##
## LEF for PtnCells ;
## created by Innovus v15.23-s045_1 on Thu Mar  5 12:03:12 2026
##

VERSION 5.8 ;

BUSBITCHARS "[]" ;
DIVIDERCHAR "/" ;

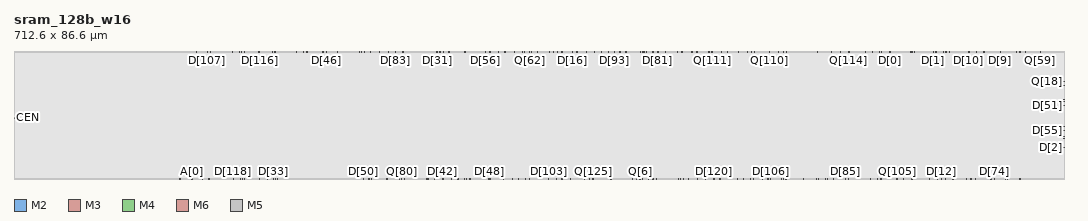
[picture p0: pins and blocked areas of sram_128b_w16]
MACRO sram_128b_w16
  CLASS BLOCK ;
  SIZE 712.6000 BY 86.6000 ;
  FOREIGN sram_128b_w16 0.0000 0.0000 ;
  ORIGIN 0 0 ;
  SYMMETRY X Y R90 ;
  PIN CLK
    DIRECTION INPUT ;
    USE SIGNAL ;
    PORT
      LAYER M2 ;
        RECT 429.4500 86.0800 429.5500 86.6000 ;
    END
  END CLK
  PIN D[127]
    DIRECTION INPUT ;
    USE SIGNAL ;
    PORT
      LAYER M2 ;
        RECT 608.6500 86.0800 608.7500 86.6000 ;
    END
  END D[127]
  PIN D[126]
    DIRECTION INPUT ;
    USE SIGNAL ;
    PORT
      LAYER M2 ;
        RECT 132.2500 0.0000 132.3500 0.5200 ;
    END
  END D[126]
  PIN D[125]
    DIRECTION INPUT ;
    USE SIGNAL ;
    PORT
      LAYER M2 ;
        RECT 390.6500 0.0000 390.7500 0.5200 ;
    END
  END D[125]
  PIN D[124]
    DIRECTION INPUT ;
    USE SIGNAL ;
    PORT
      LAYER M2 ;
        RECT 535.8500 0.0000 535.9500 0.5200 ;
    END
  END D[124]
  PIN D[123]
    DIRECTION INPUT ;
    USE SIGNAL ;
    PORT
      LAYER M2 ;
        RECT 281.4500 0.0000 281.5500 0.5200 ;
    END
  END D[123]
  PIN D[122]
    DIRECTION INPUT ;
    USE SIGNAL ;
    PORT
      LAYER M2 ;
        RECT 153.8500 0.0000 153.9500 0.5200 ;
    END
  END D[122]
  PIN D[121]
    DIRECTION INPUT ;
    USE SIGNAL ;
    PORT
      LAYER M2 ;
        RECT 546.0500 0.0000 546.1500 0.5200 ;
    END
  END D[121]
  PIN D[120]
    DIRECTION INPUT ;
    USE SIGNAL ;
    PORT
      LAYER M2 ;
        RECT 475.0500 0.0000 475.1500 0.5200 ;
    END
  END D[120]
  PIN D[119]
    DIRECTION INPUT ;
    USE SIGNAL ;
    PORT
      LAYER M2 ;
        RECT 554.6500 86.0800 554.7500 86.6000 ;
    END
  END D[119]
  PIN D[118]
    DIRECTION INPUT ;
    USE SIGNAL ;
    PORT
      LAYER M2 ;
        RECT 148.8500 0.0000 148.9500 0.5200 ;
    END
  END D[118]
  PIN D[117]
    DIRECTION INPUT ;
    USE SIGNAL ;
    PORT
      LAYER M2 ;
        RECT 453.4500 86.0800 453.5500 86.6000 ;
    END
  END D[117]
  PIN D[116]
    DIRECTION INPUT ;
    USE SIGNAL ;
    PORT
      LAYER M2 ;
        RECT 166.8500 86.0800 166.9500 86.6000 ;
    END
  END D[116]
  PIN D[115]
    DIRECTION INPUT ;
    USE SIGNAL ;
    PORT
      LAYER M2 ;
        RECT 478.6500 0.0000 478.7500 0.5200 ;
    END
  END D[115]
  PIN D[114]
    DIRECTION INPUT ;
    USE SIGNAL ;
    PORT
      LAYER M2 ;
        RECT 560.6500 86.0800 560.7500 86.6000 ;
    END
  END D[114]
  PIN D[113]
    DIRECTION INPUT ;
    USE SIGNAL ;
    PORT
      LAYER M2 ;
        RECT 545.2500 86.0800 545.3500 86.6000 ;
    END
  END D[113]
  PIN D[112]
    DIRECTION INPUT ;
    USE SIGNAL ;
    PORT
      LAYER M2 ;
        RECT 522.0500 86.0800 522.1500 86.6000 ;
    END
  END D[112]
  PIN D[111]
    DIRECTION INPUT ;
    USE SIGNAL ;
    PORT
      LAYER M2 ;
        RECT 471.6500 86.0800 471.7500 86.6000 ;
    END
  END D[111]
  PIN D[110]
    DIRECTION INPUT ;
    USE SIGNAL ;
    PORT
      LAYER M2 ;
        RECT 502.6500 86.0800 502.7500 86.6000 ;
    END
  END D[110]
  PIN D[109]
    DIRECTION INPUT ;
    USE SIGNAL ;
    PORT
      LAYER M2 ;
        RECT 291.6500 86.0800 291.7500 86.6000 ;
    END
  END D[109]
  PIN D[108]
    DIRECTION INPUT ;
    USE SIGNAL ;
    PORT
      LAYER M2 ;
        RECT 578.0500 86.0800 578.1500 86.6000 ;
    END
  END D[108]
  PIN D[107]
    DIRECTION INPUT ;
    USE SIGNAL ;
    PORT
      LAYER M2 ;
        RECT 131.2500 86.0800 131.3500 86.6000 ;
    END
  END D[107]
  PIN D[106]
    DIRECTION INPUT ;
    USE SIGNAL ;
    PORT
      LAYER M2 ;
        RECT 513.4500 0.0000 513.5500 0.5200 ;
    END
  END D[106]
  PIN D[105]
    DIRECTION INPUT ;
    USE SIGNAL ;
    PORT
      LAYER M2 ;
        RECT 599.2500 0.0000 599.3500 0.5200 ;
    END
  END D[105]
  PIN D[104]
    DIRECTION INPUT ;
    USE SIGNAL ;
    PORT
      LAYER M2 ;
        RECT 609.0500 0.0000 609.1500 0.5200 ;
    END
  END D[104]
  PIN D[103]
    DIRECTION INPUT ;
    USE SIGNAL ;
    PORT
      LAYER M2 ;
        RECT 362.8500 0.0000 362.9500 0.5200 ;
    END
  END D[103]
  PIN D[102]
    DIRECTION INPUT ;
    USE SIGNAL ;
    PORT
      LAYER M2 ;
        RECT 491.2500 0.0000 491.3500 0.5200 ;
    END
  END D[102]
  PIN D[101]
    DIRECTION INPUT ;
    USE SIGNAL ;
    PORT
      LAYER M2 ;
        RECT 520.8500 0.0000 520.9500 0.5200 ;
    END
  END D[101]
  PIN D[100]
    DIRECTION INPUT ;
    USE SIGNAL ;
    PORT
      LAYER M2 ;
        RECT 148.4500 86.0800 148.5500 86.6000 ;
    END
  END D[100]
  PIN D[99]
    DIRECTION INPUT ;
    USE SIGNAL ;
    PORT
      LAYER M2 ;
        RECT 219.6500 86.0800 219.7500 86.6000 ;
    END
  END D[99]
  PIN D[98]
    DIRECTION INPUT ;
    USE SIGNAL ;
    PORT
      LAYER M2 ;
        RECT 621.2500 0.0000 621.3500 0.5200 ;
    END
  END D[98]
  PIN D[97]
    DIRECTION INPUT ;
    USE SIGNAL ;
    PORT
      LAYER M2 ;
        RECT 237.2500 0.0000 237.3500 0.5200 ;
    END
  END D[97]
  PIN D[96]
    DIRECTION INPUT ;
    USE SIGNAL ;
    PORT
      LAYER M2 ;
        RECT 411.2500 86.0800 411.3500 86.6000 ;
    END
  END D[96]
  PIN D[95]
    DIRECTION INPUT ;
    USE SIGNAL ;
    PORT
      LAYER M2 ;
        RECT 508.0500 0.0000 508.1500 0.5200 ;
    END
  END D[95]
  PIN D[94]
    DIRECTION INPUT ;
    USE SIGNAL ;
    PORT
      LAYER M2 ;
        RECT 500.0500 0.0000 500.1500 0.5200 ;
    END
  END D[94]
  PIN D[93]
    DIRECTION INPUT ;
    USE SIGNAL ;
    PORT
      LAYER M2 ;
        RECT 407.2500 86.0800 407.3500 86.6000 ;
    END
  END D[93]
  PIN D[92]
    DIRECTION INPUT ;
    USE SIGNAL ;
    PORT
      LAYER M2 ;
        RECT 646.4500 0.0000 646.5500 0.5200 ;
    END
  END D[92]
  PIN D[91]
    DIRECTION INPUT ;
    USE SIGNAL ;
    PORT
      LAYER M2 ;
        RECT 363.2500 86.0800 363.3500 86.6000 ;
    END
  END D[91]
  PIN D[90]
    DIRECTION INPUT ;
    USE SIGNAL ;
    PORT
      LAYER M2 ;
        RECT 388.4500 86.0800 388.5500 86.6000 ;
    END
  END D[90]
  PIN D[89]
    DIRECTION INPUT ;
    USE SIGNAL ;
    PORT
      LAYER M2 ;
        RECT 294.6500 86.0800 294.7500 86.6000 ;
    END
  END D[89]
  PIN D[88]
    DIRECTION INPUT ;
    USE SIGNAL ;
    PORT
      LAYER M2 ;
        RECT 368.2500 0.0000 368.3500 0.5200 ;
    END
  END D[88]
  PIN D[87]
    DIRECTION INPUT ;
    USE SIGNAL ;
    PORT
      LAYER M2 ;
        RECT 433.6500 0.0000 433.7500 0.5200 ;
    END
  END D[87]
  PIN D[86]
    DIRECTION INPUT ;
    USE SIGNAL ;
    PORT
      LAYER M2 ;
        RECT 649.6500 0.0000 649.7500 0.5200 ;
    END
  END D[86]
  PIN D[85]
    DIRECTION INPUT ;
    USE SIGNAL ;
    PORT
      LAYER M2 ;
        RECT 564.4500 0.0000 564.5500 0.5200 ;
    END
  END D[85]
  PIN D[84]
    DIRECTION INPUT ;
    USE SIGNAL ;
    PORT
      LAYER M2 ;
        RECT 653.2500 86.0800 653.3500 86.6000 ;
    END
  END D[84]
  PIN D[83]
    DIRECTION INPUT ;
    USE SIGNAL ;
    PORT
      LAYER M2 ;
        RECT 259.0500 86.0800 259.1500 86.6000 ;
    END
  END D[83]
  PIN D[82]
    DIRECTION INPUT ;
    USE SIGNAL ;
    PORT
      LAYER M2 ;
        RECT 234.4500 86.0800 234.5500 86.6000 ;
    END
  END D[82]
  PIN D[81]
    DIRECTION INPUT ;
    USE SIGNAL ;
    PORT
      LAYER M2 ;
        RECT 436.8500 86.0800 436.9500 86.6000 ;
    END
  END D[81]
  PIN D[80]
    DIRECTION INPUT ;
    USE SIGNAL ;
    PORT
      LAYER M2 ;
        RECT 261.6500 0.0000 261.7500 0.5200 ;
    END
  END D[80]
  PIN D[79]
    DIRECTION INPUT ;
    USE SIGNAL ;
    PORT
      LAYER M2 ;
        RECT 191.4500 86.0800 191.5500 86.6000 ;
    END
  END D[79]
  PIN D[78]
    DIRECTION INPUT ;
    USE SIGNAL ;
    PORT
      LAYER M2 ;
        RECT 635.0500 86.0800 635.1500 86.6000 ;
    END
  END D[78]
  PIN D[77]
    DIRECTION INPUT ;
    USE SIGNAL ;
    PORT
      LAYER M2 ;
        RECT 342.2500 0.0000 342.3500 0.5200 ;
    END
  END D[77]
  PIN D[76]
    DIRECTION INPUT ;
    USE SIGNAL ;
    PORT
      LAYER M2 ;
        RECT 248.0500 86.0800 248.1500 86.6000 ;
    END
  END D[76]
  PIN D[75]
    DIRECTION INPUT ;
    USE SIGNAL ;
    PORT
      LAYER M2 ;
        RECT 196.4500 86.0800 196.5500 86.6000 ;
    END
  END D[75]
  PIN D[74]
    DIRECTION INPUT ;
    USE SIGNAL ;
    PORT
      LAYER M2 ;
        RECT 665.4500 0.0000 665.5500 0.5200 ;
    END
  END D[74]
  PIN D[73]
    DIRECTION INPUT ;
    USE SIGNAL ;
    PORT
      LAYER M2 ;
        RECT 323.4500 0.0000 323.5500 0.5200 ;
    END
  END D[73]
  PIN D[72]
    DIRECTION INPUT ;
    USE SIGNAL ;
    PORT
      LAYER M2 ;
        RECT 333.4500 86.0800 333.5500 86.6000 ;
    END
  END D[72]
  PIN D[71]
    DIRECTION INPUT ;
    USE SIGNAL ;
    PORT
      LAYER M2 ;
        RECT 424.2500 0.0000 424.3500 0.5200 ;
    END
  END D[71]
  PIN D[70]
    DIRECTION INPUT ;
    USE SIGNAL ;
    PORT
      LAYER M2 ;
        RECT 309.4500 0.0000 309.5500 0.5200 ;
    END
  END D[70]
  PIN D[69]
    DIRECTION INPUT ;
    USE SIGNAL ;
    PORT
      LAYER M2 ;
        RECT 680.0500 86.0800 680.1500 86.6000 ;
    END
  END D[69]
  PIN D[68]
    DIRECTION INPUT ;
    USE SIGNAL ;
    PORT
      LAYER M2 ;
        RECT 405.6500 0.0000 405.7500 0.5200 ;
    END
  END D[68]
  PIN D[67]
    DIRECTION INPUT ;
    USE SIGNAL ;
    PORT
      LAYER M2 ;
        RECT 347.0500 0.0000 347.1500 0.5200 ;
    END
  END D[67]
  PIN D[66]
    DIRECTION INPUT ;
    USE SIGNAL ;
    PORT
      LAYER M2 ;
        RECT 377.4500 0.0000 377.5500 0.5200 ;
    END
  END D[66]
  PIN D[65]
    DIRECTION INPUT ;
    USE SIGNAL ;
    PORT
      LAYER M2 ;
        RECT 323.0500 86.0800 323.1500 86.6000 ;
    END
  END D[65]
  PIN D[64]
    DIRECTION INPUT ;
    USE SIGNAL ;
    PORT
      LAYER M2 ;
        RECT 301.2500 0.0000 301.3500 0.5200 ;
    END
  END D[64]
  PIN D[63]
    DIRECTION INPUT ;
    USE SIGNAL ;
    PORT
      LAYER M2 ;
        RECT 637.2500 0.0000 637.3500 0.5200 ;
    END
  END D[63]
  PIN D[62]
    DIRECTION INPUT ;
    USE SIGNAL ;
    PORT
      LAYER M2 ;
        RECT 346.6500 86.0800 346.7500 86.6000 ;
    END
  END D[62]
  PIN D[61]
    DIRECTION INPUT ;
    USE SIGNAL ;
    PORT
      LAYER M2 ;
        RECT 153.0500 86.0800 153.1500 86.6000 ;
    END
  END D[61]
  PIN D[60]
    DIRECTION INPUT ;
    USE SIGNAL ;
    PORT
      LAYER M2 ;
        RECT 178.8500 0.0000 178.9500 0.5200 ;
    END
  END D[60]
  PIN D[59]
    DIRECTION INPUT ;
    USE SIGNAL ;
    PORT
      LAYER M2 ;
        RECT 682.2500 86.0800 682.3500 86.6000 ;
    END
  END D[59]
  PIN D[58]
    DIRECTION INPUT ;
    USE SIGNAL ;
    PORT
      LAYER M2 ;
        RECT 166.6500 0.0000 166.7500 0.5200 ;
    END
  END D[58]
  PIN D[57]
    DIRECTION INPUT ;
    USE SIGNAL ;
    PORT
      LAYER M2 ;
        RECT 552.2500 0.0000 552.3500 0.5200 ;
    END
  END D[57]
  PIN D[56]
    DIRECTION INPUT ;
    USE SIGNAL ;
    PORT
      LAYER M2 ;
        RECT 320.0500 86.0800 320.1500 86.6000 ;
    END
  END D[56]
  PIN D[55]
    DIRECTION INPUT ;
    USE SIGNAL ;
    PORT
      LAYER M3 ;
        RECT 712.0800 32.9500 712.6000 33.0500 ;
    END
  END D[55]
  PIN D[54]
    DIRECTION INPUT ;
    USE SIGNAL ;
    PORT
      LAYER M2 ;
        RECT 332.0500 0.0000 332.1500 0.5200 ;
    END
  END D[54]
  PIN D[53]
    DIRECTION INPUT ;
    USE SIGNAL ;
    PORT
      LAYER M2 ;
        RECT 427.6500 86.0800 427.7500 86.6000 ;
    END
  END D[53]
  PIN D[52]
    DIRECTION INPUT ;
    USE SIGNAL ;
    PORT
      LAYER M4 ;
        RECT 347.2500 0.0000 347.3500 0.5200 ;
    END
  END D[52]
  PIN D[51]
    DIRECTION INPUT ;
    USE SIGNAL ;
    PORT
      LAYER M3 ;
        RECT 712.0800 49.5500 712.6000 49.6500 ;
    END
  END D[51]
  PIN D[50]
    DIRECTION INPUT ;
    USE SIGNAL ;
    PORT
      LAYER M4 ;
        RECT 237.0500 0.0000 237.1500 0.5200 ;
    END
  END D[50]
  PIN D[49]
    DIRECTION INPUT ;
    USE SIGNAL ;
    PORT
      LAYER M2 ;
        RECT 237.8500 86.0800 237.9500 86.6000 ;
    END
  END D[49]
  PIN D[48]
    DIRECTION INPUT ;
    USE SIGNAL ;
    PORT
      LAYER M2 ;
        RECT 322.8500 0.0000 322.9500 0.5200 ;
    END
  END D[48]
  PIN D[47]
    DIRECTION INPUT ;
    USE SIGNAL ;
    PORT
      LAYER M2 ;
        RECT 387.2500 0.0000 387.3500 0.5200 ;
    END
  END D[47]
  PIN D[46]
    DIRECTION INPUT ;
    USE SIGNAL ;
    PORT
      LAYER M2 ;
        RECT 212.2500 86.0800 212.3500 86.6000 ;
    END
  END D[46]
  PIN D[45]
    DIRECTION INPUT ;
    USE SIGNAL ;
    PORT
      LAYER M2 ;
        RECT 454.4500 0.0000 454.5500 0.5200 ;
    END
  END D[45]
  PIN D[44]
    DIRECTION INPUT ;
    USE SIGNAL ;
    PORT
      LAYER M2 ;
        RECT 265.2500 0.0000 265.3500 0.5200 ;
    END
  END D[44]
  PIN D[43]
    DIRECTION INPUT ;
    USE SIGNAL ;
    PORT
      LAYER M2 ;
        RECT 252.6500 0.0000 252.7500 0.5200 ;
    END
  END D[43]
  PIN D[42]
    DIRECTION INPUT ;
    USE SIGNAL ;
    PORT
      LAYER M2 ;
        RECT 291.0500 0.0000 291.1500 0.5200 ;
    END
  END D[42]
  PIN D[41]
    DIRECTION INPUT ;
    USE SIGNAL ;
    PORT
      LAYER M2 ;
        RECT 280.2500 0.0000 280.3500 0.5200 ;
    END
  END D[41]
  PIN D[40]
    DIRECTION INPUT ;
    USE SIGNAL ;
    PORT
      LAYER M2 ;
        RECT 288.6500 86.0800 288.7500 86.6000 ;
    END
  END D[40]
  PIN D[39]
    DIRECTION INPUT ;
    USE SIGNAL ;
    PORT
      LAYER M2 ;
        RECT 289.6500 86.0800 289.7500 86.6000 ;
    END
  END D[39]
  PIN D[38]
    DIRECTION INPUT ;
    USE SIGNAL ;
    PORT
      LAYER M2 ;
        RECT 473.4500 86.0800 473.5500 86.6000 ;
    END
  END D[38]
  PIN D[37]
    DIRECTION INPUT ;
    USE SIGNAL ;
    PORT
      LAYER M2 ;
        RECT 175.4500 86.0800 175.5500 86.6000 ;
    END
  END D[37]
  PIN D[36]
    DIRECTION INPUT ;
    USE SIGNAL ;
    PORT
      LAYER M2 ;
        RECT 581.0500 0.0000 581.1500 0.5200 ;
    END
  END D[36]
  PIN D[35]
    DIRECTION INPUT ;
    USE SIGNAL ;
    PORT
      LAYER M2 ;
        RECT 351.2500 86.0800 351.3500 86.6000 ;
    END
  END D[35]
  PIN D[34]
    DIRECTION INPUT ;
    USE SIGNAL ;
    PORT
      LAYER M2 ;
        RECT 133.0500 86.0800 133.1500 86.6000 ;
    END
  END D[34]
  PIN D[33]
    DIRECTION INPUT ;
    USE SIGNAL ;
    PORT
      LAYER M2 ;
        RECT 175.8500 0.0000 175.9500 0.5200 ;
    END
  END D[33]
  PIN D[32]
    DIRECTION INPUT ;
    USE SIGNAL ;
    PORT
      LAYER M2 ;
        RECT 682.6500 0.0000 682.7500 0.5200 ;
    END
  END D[32]
  PIN D[31]
    DIRECTION INPUT ;
    USE SIGNAL ;
    PORT
      LAYER M2 ;
        RECT 287.0500 86.0800 287.1500 86.6000 ;
    END
  END D[31]
  PIN D[30]
    DIRECTION INPUT ;
    USE SIGNAL ;
    PORT
      LAYER M2 ;
        RECT 625.6500 86.0800 625.7500 86.6000 ;
    END
  END D[30]
  PIN D[29]
    DIRECTION INPUT ;
    USE SIGNAL ;
    PORT
      LAYER M2 ;
        RECT 586.0500 0.0000 586.1500 0.5200 ;
    END
  END D[29]
  PIN D[28]
    DIRECTION INPUT ;
    USE SIGNAL ;
    PORT
      LAYER M2 ;
        RECT 369.0500 86.0800 369.1500 86.6000 ;
    END
  END D[28]
  PIN D[27]
    DIRECTION INPUT ;
    USE SIGNAL ;
    PORT
      LAYER M2 ;
        RECT 393.6500 86.0800 393.7500 86.6000 ;
    END
  END D[27]
  PIN D[26]
    DIRECTION INPUT ;
    USE SIGNAL ;
    PORT
      LAYER M2 ;
        RECT 523.4500 0.0000 523.5500 0.5200 ;
    END
  END D[26]
  PIN D[25]
    DIRECTION INPUT ;
    USE SIGNAL ;
    PORT
      LAYER M2 ;
        RECT 460.2500 86.0800 460.3500 86.6000 ;
    END
  END D[25]
  PIN D[24]
    DIRECTION INPUT ;
    USE SIGNAL ;
    PORT
      LAYER M2 ;
        RECT 497.8500 86.0800 497.9500 86.6000 ;
    END
  END D[24]
  PIN D[23]
    DIRECTION INPUT ;
    USE SIGNAL ;
    PORT
      LAYER M2 ;
        RECT 450.4500 86.0800 450.5500 86.6000 ;
    END
  END D[23]
  PIN D[22]
    DIRECTION INPUT ;
    USE SIGNAL ;
    PORT
      LAYER M2 ;
        RECT 450.8500 0.0000 450.9500 0.5200 ;
    END
  END D[22]
  PIN D[21]
    DIRECTION INPUT ;
    USE SIGNAL ;
    PORT
      LAYER M2 ;
        RECT 603.6500 0.0000 603.7500 0.5200 ;
    END
  END D[21]
  PIN D[20]
    DIRECTION INPUT ;
    USE SIGNAL ;
    PORT
      LAYER M2 ;
        RECT 480.2500 86.0800 480.3500 86.6000 ;
    END
  END D[20]
  PIN D[19]
    DIRECTION INPUT ;
    USE SIGNAL ;
    PORT
      LAYER M2 ;
        RECT 463.6500 0.0000 463.7500 0.5200 ;
    END
  END D[19]
  PIN D[18]
    DIRECTION INPUT ;
    USE SIGNAL ;
    PORT
      LAYER M2 ;
        RECT 683.2500 86.0800 683.3500 86.6000 ;
    END
  END D[18]
  PIN D[17]
    DIRECTION INPUT ;
    USE SIGNAL ;
    PORT
      LAYER M2 ;
        RECT 518.8500 86.0800 518.9500 86.6000 ;
    END
  END D[17]
  PIN D[16]
    DIRECTION INPUT ;
    USE SIGNAL ;
    PORT
      LAYER M2 ;
        RECT 378.8500 86.0800 378.9500 86.6000 ;
    END
  END D[16]
  PIN D[15]
    DIRECTION INPUT ;
    USE SIGNAL ;
    PORT
      LAYER M2 ;
        RECT 415.2500 86.0800 415.3500 86.6000 ;
    END
  END D[15]
  PIN D[14]
    DIRECTION INPUT ;
    USE SIGNAL ;
    PORT
      LAYER M2 ;
        RECT 672.8500 0.0000 672.9500 0.5200 ;
    END
  END D[14]
  PIN D[13]
    DIRECTION INPUT ;
    USE SIGNAL ;
    PORT
      LAYER M2 ;
        RECT 433.6500 86.0800 433.7500 86.6000 ;
    END
  END D[13]
  PIN D[12]
    DIRECTION INPUT ;
    USE SIGNAL ;
    PORT
      LAYER M2 ;
        RECT 629.4500 0.0000 629.5500 0.5200 ;
    END
  END D[12]
  PIN D[11]
    DIRECTION INPUT ;
    USE SIGNAL ;
    PORT
      LAYER M2 ;
        RECT 649.2500 0.0000 649.3500 0.5200 ;
    END
  END D[11]
  PIN D[10]
    DIRECTION INPUT ;
    USE SIGNAL ;
    PORT
      LAYER M2 ;
        RECT 647.4500 86.0800 647.5500 86.6000 ;
    END
  END D[10]
  PIN D[9]
    DIRECTION INPUT ;
    USE SIGNAL ;
    PORT
      LAYER M2 ;
        RECT 669.2500 86.0800 669.3500 86.6000 ;
    END
  END D[9]
  PIN D[8]
    DIRECTION INPUT ;
    USE SIGNAL ;
    PORT
      LAYER M2 ;
        RECT 491.4500 86.0800 491.5500 86.6000 ;
    END
  END D[8]
  PIN D[7]
    DIRECTION INPUT ;
    USE SIGNAL ;
    PORT
      LAYER M2 ;
        RECT 686.2500 86.0800 686.3500 86.6000 ;
    END
  END D[7]
  PIN D[6]
    DIRECTION INPUT ;
    USE SIGNAL ;
    PORT
      LAYER M2 ;
        RECT 419.6500 0.0000 419.7500 0.5200 ;
    END
  END D[6]
  PIN D[5]
    DIRECTION INPUT ;
    USE SIGNAL ;
    PORT
      LAYER M2 ;
        RECT 422.6500 0.0000 422.7500 0.5200 ;
    END
  END D[5]
  PIN D[4]
    DIRECTION INPUT ;
    USE SIGNAL ;
    PORT
      LAYER M2 ;
        RECT 611.2500 86.0800 611.3500 86.6000 ;
    END
  END D[4]
  PIN D[3]
    DIRECTION INPUT ;
    USE SIGNAL ;
    PORT
      LAYER M2 ;
        RECT 587.4500 86.0800 587.5500 86.6000 ;
    END
  END D[3]
  PIN D[2]
    DIRECTION INPUT ;
    USE SIGNAL ;
    PORT
      LAYER M3 ;
        RECT 712.0800 21.5500 712.6000 21.6500 ;
    END
  END D[2]
  PIN D[1]
    DIRECTION INPUT ;
    USE SIGNAL ;
    PORT
      LAYER M2 ;
        RECT 623.8500 86.0800 623.9500 86.6000 ;
    END
  END D[1]
  PIN D[0]
    DIRECTION INPUT ;
    USE SIGNAL ;
    PORT
      LAYER M2 ;
        RECT 594.4500 86.0800 594.5500 86.6000 ;
    END
  END D[0]
  PIN Q[127]
    DIRECTION OUTPUT ;
    USE SIGNAL ;
    PORT
      LAYER M2 ;
        RECT 609.6500 86.0800 609.7500 86.6000 ;
    END
  END Q[127]
  PIN Q[126]
    DIRECTION OUTPUT ;
    USE SIGNAL ;
    PORT
      LAYER M2 ;
        RECT 127.8500 0.0000 127.9500 0.5200 ;
    END
  END Q[126]
  PIN Q[125]
    DIRECTION OUTPUT ;
    USE SIGNAL ;
    PORT
      LAYER M2 ;
        RECT 393.0500 0.0000 393.1500 0.5200 ;
    END
  END Q[125]
  PIN Q[124]
    DIRECTION OUTPUT ;
    USE SIGNAL ;
    PORT
      LAYER M2 ;
        RECT 544.6500 0.0000 544.7500 0.5200 ;
    END
  END Q[124]
  PIN Q[123]
    DIRECTION OUTPUT ;
    USE SIGNAL ;
    PORT
      LAYER M2 ;
        RECT 285.4500 0.0000 285.5500 0.5200 ;
    END
  END Q[123]
  PIN Q[122]
    DIRECTION OUTPUT ;
    USE SIGNAL ;
    PORT
      LAYER M2 ;
        RECT 156.6500 0.0000 156.7500 0.5200 ;
    END
  END Q[122]
  PIN Q[121]
    DIRECTION OUTPUT ;
    USE SIGNAL ;
    PORT
      LAYER M2 ;
        RECT 550.6500 0.0000 550.7500 0.5200 ;
    END
  END Q[121]
  PIN Q[120]
    DIRECTION OUTPUT ;
    USE SIGNAL ;
    PORT
      LAYER M2 ;
        RECT 479.6500 0.0000 479.7500 0.5200 ;
    END
  END Q[120]
  PIN Q[119]
    DIRECTION OUTPUT ;
    USE SIGNAL ;
    PORT
      LAYER M2 ;
        RECT 566.8500 86.0800 566.9500 86.6000 ;
    END
  END Q[119]
  PIN Q[118]
    DIRECTION OUTPUT ;
    USE SIGNAL ;
    PORT
      LAYER M2 ;
        RECT 155.0500 0.0000 155.1500 0.5200 ;
    END
  END Q[118]
  PIN Q[117]
    DIRECTION OUTPUT ;
    USE SIGNAL ;
    PORT
      LAYER M2 ;
        RECT 459.8500 86.0800 459.9500 86.6000 ;
    END
  END Q[117]
  PIN Q[116]
    DIRECTION OUTPUT ;
    USE SIGNAL ;
    PORT
      LAYER M2 ;
        RECT 166.2500 86.0800 166.3500 86.6000 ;
    END
  END Q[116]
  PIN Q[115]
    DIRECTION OUTPUT ;
    USE SIGNAL ;
    PORT
      LAYER M4 ;
        RECT 479.4500 0.0000 479.5500 0.5200 ;
    END
  END Q[115]
  PIN Q[114]
    DIRECTION OUTPUT ;
    USE SIGNAL ;
    PORT
      LAYER M2 ;
        RECT 566.4500 86.0800 566.5500 86.6000 ;
    END
  END Q[114]
  PIN Q[113]
    DIRECTION OUTPUT ;
    USE SIGNAL ;
    PORT
      LAYER M4 ;
        RECT 554.8500 86.0800 554.9500 86.6000 ;
    END
  END Q[113]
  PIN Q[112]
    DIRECTION OUTPUT ;
    USE SIGNAL ;
    PORT
      LAYER M2 ;
        RECT 524.0500 86.0800 524.1500 86.6000 ;
    END
  END Q[112]
  PIN Q[111]
    DIRECTION OUTPUT ;
    USE SIGNAL ;
    PORT
      LAYER M2 ;
        RECT 473.8500 86.0800 473.9500 86.6000 ;
    END
  END Q[111]
  PIN Q[110]
    DIRECTION OUTPUT ;
    USE SIGNAL ;
    PORT
      LAYER M2 ;
        RECT 512.4500 86.0800 512.5500 86.6000 ;
    END
  END Q[110]
  PIN Q[109]
    DIRECTION OUTPUT ;
    USE SIGNAL ;
    PORT
      LAYER M2 ;
        RECT 295.4500 86.0800 295.5500 86.6000 ;
    END
  END Q[109]
  PIN Q[108]
    DIRECTION OUTPUT ;
    USE SIGNAL ;
    PORT
      LAYER M2 ;
        RECT 582.4500 86.0800 582.5500 86.6000 ;
    END
  END Q[108]
  PIN Q[107]
    DIRECTION OUTPUT ;
    USE SIGNAL ;
    PORT
      LAYER M2 ;
        RECT 123.6500 86.0800 123.7500 86.6000 ;
    END
  END Q[107]
  PIN Q[106]
    DIRECTION OUTPUT ;
    USE SIGNAL ;
    PORT
      LAYER M2 ;
        RECT 511.6500 0.0000 511.7500 0.5200 ;
    END
  END Q[106]
  PIN Q[105]
    DIRECTION OUTPUT ;
    USE SIGNAL ;
    PORT
      LAYER M4 ;
        RECT 599.4500 0.0000 599.5500 0.5200 ;
    END
  END Q[105]
  PIN Q[104]
    DIRECTION OUTPUT ;
    USE SIGNAL ;
    PORT
      LAYER M2 ;
        RECT 609.8500 0.0000 609.9500 0.5200 ;
    END
  END Q[104]
  PIN Q[103]
    DIRECTION OUTPUT ;
    USE SIGNAL ;
    PORT
      LAYER M2 ;
        RECT 371.8500 86.0800 371.9500 86.6000 ;
    END
  END Q[103]
  PIN Q[102]
    DIRECTION OUTPUT ;
    USE SIGNAL ;
    PORT
      LAYER M2 ;
        RECT 495.0500 0.0000 495.1500 0.5200 ;
    END
  END Q[102]
  PIN Q[101]
    DIRECTION OUTPUT ;
    USE SIGNAL ;
    PORT
      LAYER M2 ;
        RECT 523.8500 0.0000 523.9500 0.5200 ;
    END
  END Q[101]
  PIN Q[100]
    DIRECTION OUTPUT ;
    USE SIGNAL ;
    PORT
      LAYER M2 ;
        RECT 154.4500 86.0800 154.5500 86.6000 ;
    END
  END Q[100]
  PIN Q[99]
    DIRECTION OUTPUT ;
    USE SIGNAL ;
    PORT
      LAYER M4 ;
        RECT 219.6500 86.0800 219.7500 86.6000 ;
    END
  END Q[99]
  PIN Q[98]
    DIRECTION OUTPUT ;
    USE SIGNAL ;
    PORT
      LAYER M2 ;
        RECT 626.6500 0.0000 626.7500 0.5200 ;
    END
  END Q[98]
  PIN Q[97]
    DIRECTION OUTPUT ;
    USE SIGNAL ;
    PORT
      LAYER M2 ;
        RECT 242.4500 0.0000 242.5500 0.5200 ;
    END
  END Q[97]
  PIN Q[96]
    DIRECTION OUTPUT ;
    USE SIGNAL ;
    PORT
      LAYER M2 ;
        RECT 425.0500 86.0800 425.1500 86.6000 ;
    END
  END Q[96]
  PIN Q[95]
    DIRECTION OUTPUT ;
    USE SIGNAL ;
    PORT
      LAYER M2 ;
        RECT 512.0500 0.0000 512.1500 0.5200 ;
    END
  END Q[95]
  PIN Q[94]
    DIRECTION OUTPUT ;
    USE SIGNAL ;
    PORT
      LAYER M2 ;
        RECT 501.8500 0.0000 501.9500 0.5200 ;
    END
  END Q[94]
  PIN Q[93]
    DIRECTION OUTPUT ;
    USE SIGNAL ;
    PORT
      LAYER M2 ;
        RECT 403.2500 86.0800 403.3500 86.6000 ;
    END
  END Q[93]
  PIN Q[92]
    DIRECTION OUTPUT ;
    USE SIGNAL ;
    PORT
      LAYER M4 ;
        RECT 647.4500 86.0800 647.5500 86.6000 ;
    END
  END Q[92]
  PIN Q[91]
    DIRECTION OUTPUT ;
    USE SIGNAL ;
    PORT
      LAYER M2 ;
        RECT 365.8500 86.0800 365.9500 86.6000 ;
    END
  END Q[91]
  PIN Q[90]
    DIRECTION OUTPUT ;
    USE SIGNAL ;
    PORT
      LAYER M2 ;
        RECT 382.0500 86.0800 382.1500 86.6000 ;
    END
  END Q[90]
  PIN Q[89]
    DIRECTION OUTPUT ;
    USE SIGNAL ;
    PORT
      LAYER M2 ;
        RECT 306.2500 86.0800 306.3500 86.6000 ;
    END
  END Q[89]
  PIN Q[88]
    DIRECTION OUTPUT ;
    USE SIGNAL ;
    PORT
      LAYER M2 ;
        RECT 371.8500 0.0000 371.9500 0.5200 ;
    END
  END Q[88]
  PIN Q[87]
    DIRECTION OUTPUT ;
    USE SIGNAL ;
    PORT
      LAYER M2 ;
        RECT 430.6500 0.0000 430.7500 0.5200 ;
    END
  END Q[87]
  PIN Q[86]
    DIRECTION OUTPUT ;
    USE SIGNAL ;
    PORT
      LAYER M4 ;
        RECT 653.4500 86.0800 653.5500 86.6000 ;
    END
  END Q[86]
  PIN Q[85]
    DIRECTION OUTPUT ;
    USE SIGNAL ;
    PORT
      LAYER M2 ;
        RECT 566.0500 0.0000 566.1500 0.5200 ;
    END
  END Q[85]
  PIN Q[84]
    DIRECTION OUTPUT ;
    USE SIGNAL ;
    PORT
      LAYER M2 ;
        RECT 658.2500 86.0800 658.3500 86.6000 ;
    END
  END Q[84]
  PIN Q[83]
    DIRECTION OUTPUT ;
    USE SIGNAL ;
    PORT
      LAYER M2 ;
        RECT 263.4500 86.0800 263.5500 86.6000 ;
    END
  END Q[83]
  PIN Q[82]
    DIRECTION OUTPUT ;
    USE SIGNAL ;
    PORT
      LAYER M2 ;
        RECT 236.0500 86.0800 236.1500 86.6000 ;
    END
  END Q[82]
  PIN Q[81]
    DIRECTION OUTPUT ;
    USE SIGNAL ;
    PORT
      LAYER M2 ;
        RECT 441.8500 86.0800 441.9500 86.6000 ;
    END
  END Q[81]
  PIN Q[80]
    DIRECTION OUTPUT ;
    USE SIGNAL ;
    PORT
      LAYER M2 ;
        RECT 263.0500 0.0000 263.1500 0.5200 ;
    END
  END Q[80]
  PIN Q[79]
    DIRECTION OUTPUT ;
    USE SIGNAL ;
    PORT
      LAYER M2 ;
        RECT 198.2500 86.0800 198.3500 86.6000 ;
    END
  END Q[79]
  PIN Q[78]
    DIRECTION OUTPUT ;
    USE SIGNAL ;
    PORT
      LAYER M2 ;
        RECT 632.4500 86.0800 632.5500 86.6000 ;
    END
  END Q[78]
  PIN Q[77]
    DIRECTION OUTPUT ;
    USE SIGNAL ;
    PORT
      LAYER M2 ;
        RECT 339.6500 86.0800 339.7500 86.6000 ;
    END
  END Q[77]
  PIN Q[76]
    DIRECTION OUTPUT ;
    USE SIGNAL ;
    PORT
      LAYER M2 ;
        RECT 253.8500 86.0800 253.9500 86.6000 ;
    END
  END Q[76]
  PIN Q[75]
    DIRECTION OUTPUT ;
    USE SIGNAL ;
    PORT
      LAYER M2 ;
        RECT 199.0500 86.0800 199.1500 86.6000 ;
    END
  END Q[75]
  PIN Q[74]
    DIRECTION OUTPUT ;
    USE SIGNAL ;
    PORT
      LAYER M2 ;
        RECT 663.0500 0.0000 663.1500 0.5200 ;
    END
  END Q[74]
  PIN Q[73]
    DIRECTION OUTPUT ;
    USE SIGNAL ;
    PORT
      LAYER M2 ;
        RECT 328.6500 86.0800 328.7500 86.6000 ;
    END
  END Q[73]
  PIN Q[72]
    DIRECTION OUTPUT ;
    USE SIGNAL ;
    PORT
      LAYER M2 ;
        RECT 333.0500 86.0800 333.1500 86.6000 ;
    END
  END Q[72]
  PIN Q[71]
    DIRECTION OUTPUT ;
    USE SIGNAL ;
    PORT
      LAYER M2 ;
        RECT 435.8500 0.0000 435.9500 0.5200 ;
    END
  END Q[71]
  PIN Q[70]
    DIRECTION OUTPUT ;
    USE SIGNAL ;
    PORT
      LAYER M2 ;
        RECT 307.0500 0.0000 307.1500 0.5200 ;
    END
  END Q[70]
  PIN Q[69]
    DIRECTION OUTPUT ;
    USE SIGNAL ;
    PORT
      LAYER M3 ;
        RECT 712.0800 63.3500 712.6000 63.4500 ;
    END
  END Q[69]
  PIN Q[68]
    DIRECTION OUTPUT ;
    USE SIGNAL ;
    PORT
      LAYER M2 ;
        RECT 405.0500 0.0000 405.1500 0.5200 ;
    END
  END Q[68]
  PIN Q[67]
    DIRECTION OUTPUT ;
    USE SIGNAL ;
    PORT
      LAYER M2 ;
        RECT 345.0500 86.0800 345.1500 86.6000 ;
    END
  END Q[67]
  PIN Q[66]
    DIRECTION OUTPUT ;
    USE SIGNAL ;
    PORT
      LAYER M2 ;
        RECT 372.2500 86.0800 372.3500 86.6000 ;
    END
  END Q[66]
  PIN Q[65]
    DIRECTION OUTPUT ;
    USE SIGNAL ;
    PORT
      LAYER M2 ;
        RECT 329.0500 86.0800 329.1500 86.6000 ;
    END
  END Q[65]
  PIN Q[64]
    DIRECTION OUTPUT ;
    USE SIGNAL ;
    PORT
      LAYER M2 ;
        RECT 305.8500 0.0000 305.9500 0.5200 ;
    END
  END Q[64]
  PIN Q[63]
    DIRECTION OUTPUT ;
    USE SIGNAL ;
    PORT
      LAYER M2 ;
        RECT 631.8500 0.0000 631.9500 0.5200 ;
    END
  END Q[63]
  PIN Q[62]
    DIRECTION OUTPUT ;
    USE SIGNAL ;
    PORT
      LAYER M2 ;
        RECT 349.8500 86.0800 349.9500 86.6000 ;
    END
  END Q[62]
  PIN Q[61]
    DIRECTION OUTPUT ;
    USE SIGNAL ;
    PORT
      LAYER M2 ;
        RECT 156.4500 86.0800 156.5500 86.6000 ;
    END
  END Q[61]
  PIN Q[60]
    DIRECTION OUTPUT ;
    USE SIGNAL ;
    PORT
      LAYER M2 ;
        RECT 177.4500 0.0000 177.5500 0.5200 ;
    END
  END Q[60]
  PIN Q[59]
    DIRECTION OUTPUT ;
    USE SIGNAL ;
    PORT
      LAYER M2 ;
        RECT 696.4500 86.0800 696.5500 86.6000 ;
    END
  END Q[59]
  PIN Q[58]
    DIRECTION OUTPUT ;
    USE SIGNAL ;
    PORT
      LAYER M2 ;
        RECT 171.8500 0.0000 171.9500 0.5200 ;
    END
  END Q[58]
  PIN Q[57]
    DIRECTION OUTPUT ;
    USE SIGNAL ;
    PORT
      LAYER M2 ;
        RECT 556.0500 0.0000 556.1500 0.5200 ;
    END
  END Q[57]
  PIN Q[56]
    DIRECTION OUTPUT ;
    USE SIGNAL ;
    PORT
      LAYER M2 ;
        RECT 322.6500 86.0800 322.7500 86.6000 ;
    END
  END Q[56]
  PIN Q[55]
    DIRECTION OUTPUT ;
    USE SIGNAL ;
    PORT
      LAYER M3 ;
        RECT 712.0800 35.7500 712.6000 35.8500 ;
    END
  END Q[55]
  PIN Q[54]
    DIRECTION OUTPUT ;
    USE SIGNAL ;
    PORT
      LAYER M2 ;
        RECT 338.4500 0.0000 338.5500 0.5200 ;
    END
  END Q[54]
  PIN Q[53]
    DIRECTION OUTPUT ;
    USE SIGNAL ;
    PORT
      LAYER M2 ;
        RECT 427.2500 86.0800 427.3500 86.6000 ;
    END
  END Q[53]
  PIN Q[52]
    DIRECTION OUTPUT ;
    USE SIGNAL ;
    PORT
      LAYER M2 ;
        RECT 349.8500 0.0000 349.9500 0.5200 ;
    END
  END Q[52]
  PIN Q[51]
    DIRECTION OUTPUT ;
    USE SIGNAL ;
    PORT
      LAYER M3 ;
        RECT 712.0800 53.7500 712.6000 53.8500 ;
    END
  END Q[51]
  PIN Q[50]
    DIRECTION OUTPUT ;
    USE SIGNAL ;
    PORT
      LAYER M2 ;
        RECT 240.8500 0.0000 240.9500 0.5200 ;
    END
  END Q[50]
  PIN Q[49]
    DIRECTION OUTPUT ;
    USE SIGNAL ;
    PORT
      LAYER M2 ;
        RECT 242.0500 86.0800 242.1500 86.6000 ;
    END
  END Q[49]
  PIN Q[48]
    DIRECTION OUTPUT ;
    USE SIGNAL ;
    PORT
      LAYER M2 ;
        RECT 322.2500 0.0000 322.3500 0.5200 ;
    END
  END Q[48]
  PIN Q[47]
    DIRECTION OUTPUT ;
    USE SIGNAL ;
    PORT
      LAYER M2 ;
        RECT 392.4500 0.0000 392.5500 0.5200 ;
    END
  END Q[47]
  PIN Q[46]
    DIRECTION OUTPUT ;
    USE SIGNAL ;
    PORT
      LAYER M2 ;
        RECT 209.6500 86.0800 209.7500 86.6000 ;
    END
  END Q[46]
  PIN Q[45]
    DIRECTION OUTPUT ;
    USE SIGNAL ;
    PORT
      LAYER M2 ;
        RECT 457.8500 0.0000 457.9500 0.5200 ;
    END
  END Q[45]
  PIN Q[44]
    DIRECTION OUTPUT ;
    USE SIGNAL ;
    PORT
      LAYER M2 ;
        RECT 264.4500 86.0800 264.5500 86.6000 ;
    END
  END Q[44]
  PIN Q[43]
    DIRECTION OUTPUT ;
    USE SIGNAL ;
    PORT
      LAYER M2 ;
        RECT 253.0500 0.0000 253.1500 0.5200 ;
    END
  END Q[43]
  PIN Q[42]
    DIRECTION OUTPUT ;
    USE SIGNAL ;
    PORT
      LAYER M2 ;
        RECT 296.6500 0.0000 296.7500 0.5200 ;
    END
  END Q[42]
  PIN Q[41]
    DIRECTION OUTPUT ;
    USE SIGNAL ;
    PORT
      LAYER M4 ;
        RECT 285.4500 0.0000 285.5500 0.5200 ;
    END
  END Q[41]
  PIN Q[40]
    DIRECTION OUTPUT ;
    USE SIGNAL ;
    PORT
      LAYER M2 ;
        RECT 305.8500 86.0800 305.9500 86.6000 ;
    END
  END Q[40]
  PIN Q[39]
    DIRECTION OUTPUT ;
    USE SIGNAL ;
    PORT
      LAYER M4 ;
        RECT 295.4500 86.0800 295.5500 86.6000 ;
    END
  END Q[39]
  PIN Q[38]
    DIRECTION OUTPUT ;
    USE SIGNAL ;
    PORT
      LAYER M4 ;
        RECT 480.2500 86.0800 480.3500 86.6000 ;
    END
  END Q[38]
  PIN Q[37]
    DIRECTION OUTPUT ;
    USE SIGNAL ;
    PORT
      LAYER M2 ;
        RECT 177.0500 86.0800 177.1500 86.6000 ;
    END
  END Q[37]
  PIN Q[36]
    DIRECTION OUTPUT ;
    USE SIGNAL ;
    PORT
      LAYER M2 ;
        RECT 588.0500 0.0000 588.1500 0.5200 ;
    END
  END Q[36]
  PIN Q[35]
    DIRECTION OUTPUT ;
    USE SIGNAL ;
    PORT
      LAYER M2 ;
        RECT 355.4500 86.0800 355.5500 86.6000 ;
    END
  END Q[35]
  PIN Q[34]
    DIRECTION OUTPUT ;
    USE SIGNAL ;
    PORT
      LAYER M2 ;
        RECT 124.0500 86.0800 124.1500 86.6000 ;
    END
  END Q[34]
  PIN Q[33]
    DIRECTION OUTPUT ;
    USE SIGNAL ;
    PORT
      LAYER M4 ;
        RECT 177.0500 86.0800 177.1500 86.6000 ;
    END
  END Q[33]
  PIN Q[32]
    DIRECTION OUTPUT ;
    USE SIGNAL ;
    PORT
      LAYER M3 ;
        RECT 712.0800 27.3500 712.6000 27.4500 ;
    END
  END Q[32]
  PIN Q[31]
    DIRECTION OUTPUT ;
    USE SIGNAL ;
    PORT
      LAYER M6 ;
        RECT 295.4500 86.0800 295.5500 86.6000 ;
    END
  END Q[31]
  PIN Q[30]
    DIRECTION OUTPUT ;
    USE SIGNAL ;
    PORT
      LAYER M2 ;
        RECT 630.6500 86.0800 630.7500 86.6000 ;
    END
  END Q[30]
  PIN Q[29]
    DIRECTION OUTPUT ;
    USE SIGNAL ;
    PORT
      LAYER M2 ;
        RECT 588.4500 0.0000 588.5500 0.5200 ;
    END
  END Q[29]
  PIN Q[28]
    DIRECTION OUTPUT ;
    USE SIGNAL ;
    PORT
      LAYER M2 ;
        RECT 371.4500 86.0800 371.5500 86.6000 ;
    END
  END Q[28]
  PIN Q[27]
    DIRECTION OUTPUT ;
    USE SIGNAL ;
    PORT
      LAYER M2 ;
        RECT 398.8500 86.0800 398.9500 86.6000 ;
    END
  END Q[27]
  PIN Q[26]
    DIRECTION OUTPUT ;
    USE SIGNAL ;
    PORT
      LAYER M2 ;
        RECT 522.4500 0.0000 522.5500 0.5200 ;
    END
  END Q[26]
  PIN Q[25]
    DIRECTION OUTPUT ;
    USE SIGNAL ;
    PORT
      LAYER M2 ;
        RECT 463.4500 86.0800 463.5500 86.6000 ;
    END
  END Q[25]
  PIN Q[24]
    DIRECTION OUTPUT ;
    USE SIGNAL ;
    PORT
      LAYER M2 ;
        RECT 502.2500 86.0800 502.3500 86.6000 ;
    END
  END Q[24]
  PIN Q[23]
    DIRECTION OUTPUT ;
    USE SIGNAL ;
    PORT
      LAYER M2 ;
        RECT 453.0500 86.0800 453.1500 86.6000 ;
    END
  END Q[23]
  PIN Q[22]
    DIRECTION OUTPUT ;
    USE SIGNAL ;
    PORT
      LAYER M2 ;
        RECT 452.4500 0.0000 452.5500 0.5200 ;
    END
  END Q[22]
  PIN Q[21]
    DIRECTION OUTPUT ;
    USE SIGNAL ;
    PORT
      LAYER M2 ;
        RECT 609.0500 86.0800 609.1500 86.6000 ;
    END
  END Q[21]
  PIN Q[20]
    DIRECTION OUTPUT ;
    USE SIGNAL ;
    PORT
      LAYER M2 ;
        RECT 484.2500 86.0800 484.3500 86.6000 ;
    END
  END Q[20]
  PIN Q[19]
    DIRECTION OUTPUT ;
    USE SIGNAL ;
    PORT
      LAYER M2 ;
        RECT 469.4500 0.0000 469.5500 0.5200 ;
    END
  END Q[19]
  PIN Q[18]
    DIRECTION OUTPUT ;
    USE SIGNAL ;
    PORT
      LAYER M3 ;
        RECT 712.0800 66.1500 712.6000 66.2500 ;
    END
  END Q[18]
  PIN Q[17]
    DIRECTION OUTPUT ;
    USE SIGNAL ;
    PORT
      LAYER M2 ;
        RECT 522.4500 86.0800 522.5500 86.6000 ;
    END
  END Q[17]
  PIN Q[16]
    DIRECTION OUTPUT ;
    USE SIGNAL ;
    PORT
      LAYER M4 ;
        RECT 372.2500 86.0800 372.3500 86.6000 ;
    END
  END Q[16]
  PIN Q[15]
    DIRECTION OUTPUT ;
    USE SIGNAL ;
    PORT
      LAYER M2 ;
        RECT 426.2500 86.0800 426.3500 86.6000 ;
    END
  END Q[15]
  PIN Q[14]
    DIRECTION OUTPUT ;
    USE SIGNAL ;
    PORT
      LAYER M2 ;
        RECT 674.4500 0.0000 674.5500 0.5200 ;
    END
  END Q[14]
  PIN Q[13]
    DIRECTION OUTPUT ;
    USE SIGNAL ;
    PORT
      LAYER M2 ;
        RECT 437.2500 86.0800 437.3500 86.6000 ;
    END
  END Q[13]
  PIN Q[12]
    DIRECTION OUTPUT ;
    USE SIGNAL ;
    PORT
      LAYER M4 ;
        RECT 631.8500 0.0000 631.9500 0.5200 ;
    END
  END Q[12]
  PIN Q[11]
    DIRECTION OUTPUT ;
    USE SIGNAL ;
    PORT
      LAYER M2 ;
        RECT 652.2500 0.0000 652.3500 0.5200 ;
    END
  END Q[11]
  PIN Q[10]
    DIRECTION OUTPUT ;
    USE SIGNAL ;
    PORT
      LAYER M2 ;
        RECT 648.0500 86.0800 648.1500 86.6000 ;
    END
  END Q[10]
  PIN Q[9]
    DIRECTION OUTPUT ;
    USE SIGNAL ;
    PORT
      LAYER M3 ;
        RECT 712.0800 52.5500 712.6000 52.6500 ;
    END
  END Q[9]
  PIN Q[8]
    DIRECTION OUTPUT ;
    USE SIGNAL ;
    PORT
      LAYER M2 ;
        RECT 500.6500 86.0800 500.7500 86.6000 ;
    END
  END Q[8]
  PIN Q[7]
    DIRECTION OUTPUT ;
    USE SIGNAL ;
    PORT
      LAYER M4 ;
        RECT 696.4500 86.0800 696.5500 86.6000 ;
    END
  END Q[7]
  PIN Q[6]
    DIRECTION OUTPUT ;
    USE SIGNAL ;
    PORT
      LAYER M2 ;
        RECT 425.0500 0.0000 425.1500 0.5200 ;
    END
  END Q[6]
  PIN Q[5]
    DIRECTION OUTPUT ;
    USE SIGNAL ;
    PORT
      LAYER M2 ;
        RECT 426.2500 0.0000 426.3500 0.5200 ;
    END
  END Q[5]
  PIN Q[4]
    DIRECTION OUTPUT ;
    USE SIGNAL ;
    PORT
      LAYER M4 ;
        RECT 609.0500 86.0800 609.1500 86.6000 ;
    END
  END Q[4]
  PIN Q[3]
    DIRECTION OUTPUT ;
    USE SIGNAL ;
    PORT
      LAYER M2 ;
        RECT 588.8500 86.0800 588.9500 86.6000 ;
    END
  END Q[3]
  PIN Q[2]
    DIRECTION OUTPUT ;
    USE SIGNAL ;
    PORT
      LAYER M3 ;
        RECT 712.0800 28.5500 712.6000 28.6500 ;
    END
  END Q[2]
  PIN Q[1]
    DIRECTION OUTPUT ;
    USE SIGNAL ;
    PORT
      LAYER M2 ;
        RECT 626.2500 86.0800 626.3500 86.6000 ;
    END
  END Q[1]
  PIN Q[0]
    DIRECTION OUTPUT ;
    USE SIGNAL ;
    PORT
      LAYER M2 ;
        RECT 593.8500 86.0800 593.9500 86.6000 ;
    END
  END Q[0]
  PIN CEN
    DIRECTION INPUT ;
    USE SIGNAL ;
    PORT
      LAYER M3 ;
        RECT 0.0000 41.3500 0.5200 41.4500 ;
    END
  END CEN
  PIN WEN
    DIRECTION INPUT ;
    USE SIGNAL ;
    PORT
      LAYER M5 ;
        RECT 0.0000 41.3500 0.5200 41.4500 ;
    END
  END WEN
  PIN A[3]
    DIRECTION INPUT ;
    USE SIGNAL ;
    PORT
      LAYER M2 ;
        RECT 121.2500 0.0000 121.3500 0.5200 ;
    END
  END A[3]
  PIN A[2]
    DIRECTION INPUT ;
    USE SIGNAL ;
    PORT
      LAYER M2 ;
        RECT 112.8500 0.0000 112.9500 0.5200 ;
    END
  END A[2]
  PIN A[1]
    DIRECTION INPUT ;
    USE SIGNAL ;
    PORT
      LAYER M4 ;
        RECT 112.6500 0.0000 112.7500 0.5200 ;
    END
  END A[1]
  PIN A[0]
    DIRECTION INPUT ;
    USE SIGNAL ;
    PORT
      LAYER M2 ;
        RECT 120.6500 0.0000 120.7500 0.5200 ;
    END
  END A[0]
  OBS
    LAYER M1 ;
      RECT 0.0000 0.0000 712.6000 86.6000 ;
    LAYER M2 ;
      RECT 696.6500 85.9800 712.6000 86.6000 ;
      RECT 686.4500 85.9800 696.3500 86.6000 ;
      RECT 683.4500 85.9800 686.1500 86.6000 ;
      RECT 682.4500 85.9800 683.1500 86.6000 ;
      RECT 680.2500 85.9800 682.1500 86.6000 ;
      RECT 669.4500 85.9800 679.9500 86.6000 ;
      RECT 658.4500 85.9800 669.1500 86.6000 ;
      RECT 653.4500 85.9800 658.1500 86.6000 ;
      RECT 648.2500 85.9800 653.1500 86.6000 ;
      RECT 647.6500 85.9800 647.9500 86.6000 ;
      RECT 635.2500 85.9800 647.3500 86.6000 ;
      RECT 632.6500 85.9800 634.9500 86.6000 ;
      RECT 630.8500 85.9800 632.3500 86.6000 ;
      RECT 626.4500 85.9800 630.5500 86.6000 ;
      RECT 625.8500 85.9800 626.1500 86.6000 ;
      RECT 624.0500 85.9800 625.5500 86.6000 ;
      RECT 611.4500 85.9800 623.7500 86.6000 ;
      RECT 609.8500 85.9800 611.1500 86.6000 ;
      RECT 609.2500 85.9800 609.5500 86.6000 ;
      RECT 608.8500 85.9800 608.9500 86.6000 ;
      RECT 594.6500 85.9800 608.5500 86.6000 ;
      RECT 594.0500 85.9800 594.3500 86.6000 ;
      RECT 589.0500 85.9800 593.7500 86.6000 ;
      RECT 587.6500 85.9800 588.7500 86.6000 ;
      RECT 582.6500 85.9800 587.3500 86.6000 ;
      RECT 578.2500 85.9800 582.3500 86.6000 ;
      RECT 567.0500 85.9800 577.9500 86.6000 ;
      RECT 566.6500 85.9800 566.7500 86.6000 ;
      RECT 560.8500 85.9800 566.3500 86.6000 ;
      RECT 554.8500 85.9800 560.5500 86.6000 ;
      RECT 545.4500 85.9800 554.5500 86.6000 ;
      RECT 524.2500 85.9800 545.1500 86.6000 ;
      RECT 522.6500 85.9800 523.9500 86.6000 ;
      RECT 522.2500 85.9800 522.3500 86.6000 ;
      RECT 519.0500 85.9800 521.9500 86.6000 ;
      RECT 512.6500 85.9800 518.7500 86.6000 ;
      RECT 502.8500 85.9800 512.3500 86.6000 ;
      RECT 502.4500 85.9800 502.5500 86.6000 ;
      RECT 500.8500 85.9800 502.1500 86.6000 ;
      RECT 498.0500 85.9800 500.5500 86.6000 ;
      RECT 491.6500 85.9800 497.7500 86.6000 ;
      RECT 484.4500 85.9800 491.3500 86.6000 ;
      RECT 480.4500 85.9800 484.1500 86.6000 ;
      RECT 474.0500 85.9800 480.1500 86.6000 ;
      RECT 473.6500 85.9800 473.7500 86.6000 ;
      RECT 471.8500 85.9800 473.3500 86.6000 ;
      RECT 463.6500 85.9800 471.5500 86.6000 ;
      RECT 460.4500 85.9800 463.3500 86.6000 ;
      RECT 460.0500 85.9800 460.1500 86.6000 ;
      RECT 453.6500 85.9800 459.7500 86.6000 ;
      RECT 453.2500 85.9800 453.3500 86.6000 ;
      RECT 450.6500 85.9800 452.9500 86.6000 ;
      RECT 442.0500 85.9800 450.3500 86.6000 ;
      RECT 437.4500 85.9800 441.7500 86.6000 ;
      RECT 437.0500 85.9800 437.1500 86.6000 ;
      RECT 433.8500 85.9800 436.7500 86.6000 ;
      RECT 429.6500 85.9800 433.5500 86.6000 ;
      RECT 427.8500 85.9800 429.3500 86.6000 ;
      RECT 427.4500 85.9800 427.5500 86.6000 ;
      RECT 426.4500 85.9800 427.1500 86.6000 ;
      RECT 425.2500 85.9800 426.1500 86.6000 ;
      RECT 415.4500 85.9800 424.9500 86.6000 ;
      RECT 411.4500 85.9800 415.1500 86.6000 ;
      RECT 407.4500 85.9800 411.1500 86.6000 ;
      RECT 403.4500 85.9800 407.1500 86.6000 ;
      RECT 399.0500 85.9800 403.1500 86.6000 ;
      RECT 393.8500 85.9800 398.7500 86.6000 ;
      RECT 388.6500 85.9800 393.5500 86.6000 ;
      RECT 382.2500 85.9800 388.3500 86.6000 ;
      RECT 379.0500 85.9800 381.9500 86.6000 ;
      RECT 372.4500 85.9800 378.7500 86.6000 ;
      RECT 372.0500 85.9800 372.1500 86.6000 ;
      RECT 371.6500 85.9800 371.7500 86.6000 ;
      RECT 369.2500 85.9800 371.3500 86.6000 ;
      RECT 366.0500 85.9800 368.9500 86.6000 ;
      RECT 363.4500 85.9800 365.7500 86.6000 ;
      RECT 355.6500 85.9800 363.1500 86.6000 ;
      RECT 351.4500 85.9800 355.3500 86.6000 ;
      RECT 350.0500 85.9800 351.1500 86.6000 ;
      RECT 346.8500 85.9800 349.7500 86.6000 ;
      RECT 345.2500 85.9800 346.5500 86.6000 ;
      RECT 339.8500 85.9800 344.9500 86.6000 ;
      RECT 333.6500 85.9800 339.5500 86.6000 ;
      RECT 333.2500 85.9800 333.3500 86.6000 ;
      RECT 329.2500 85.9800 332.9500 86.6000 ;
      RECT 328.8500 85.9800 328.9500 86.6000 ;
      RECT 323.2500 85.9800 328.5500 86.6000 ;
      RECT 322.8500 85.9800 322.9500 86.6000 ;
      RECT 320.2500 85.9800 322.5500 86.6000 ;
      RECT 306.4500 85.9800 319.9500 86.6000 ;
      RECT 306.0500 85.9800 306.1500 86.6000 ;
      RECT 295.6500 85.9800 305.7500 86.6000 ;
      RECT 294.8500 85.9800 295.3500 86.6000 ;
      RECT 291.8500 85.9800 294.5500 86.6000 ;
      RECT 289.8500 85.9800 291.5500 86.6000 ;
      RECT 288.8500 85.9800 289.5500 86.6000 ;
      RECT 287.2500 85.9800 288.5500 86.6000 ;
      RECT 264.6500 85.9800 286.9500 86.6000 ;
      RECT 263.6500 85.9800 264.3500 86.6000 ;
      RECT 259.2500 85.9800 263.3500 86.6000 ;
      RECT 254.0500 85.9800 258.9500 86.6000 ;
      RECT 248.2500 85.9800 253.7500 86.6000 ;
      RECT 242.2500 85.9800 247.9500 86.6000 ;
      RECT 238.0500 85.9800 241.9500 86.6000 ;
      RECT 236.2500 85.9800 237.7500 86.6000 ;
      RECT 234.6500 85.9800 235.9500 86.6000 ;
      RECT 219.8500 85.9800 234.3500 86.6000 ;
      RECT 212.4500 85.9800 219.5500 86.6000 ;
      RECT 209.8500 85.9800 212.1500 86.6000 ;
      RECT 199.2500 85.9800 209.5500 86.6000 ;
      RECT 198.4500 85.9800 198.9500 86.6000 ;
      RECT 196.6500 85.9800 198.1500 86.6000 ;
      RECT 191.6500 85.9800 196.3500 86.6000 ;
      RECT 177.2500 85.9800 191.3500 86.6000 ;
      RECT 175.6500 85.9800 176.9500 86.6000 ;
      RECT 167.0500 85.9800 175.3500 86.6000 ;
      RECT 166.4500 85.9800 166.7500 86.6000 ;
      RECT 156.6500 85.9800 166.1500 86.6000 ;
      RECT 154.6500 85.9800 156.3500 86.6000 ;
      RECT 153.2500 85.9800 154.3500 86.6000 ;
      RECT 148.6500 85.9800 152.9500 86.6000 ;
      RECT 133.2500 85.9800 148.3500 86.6000 ;
      RECT 131.4500 85.9800 132.9500 86.6000 ;
      RECT 124.2500 85.9800 131.1500 86.6000 ;
      RECT 123.8500 85.9800 123.9500 86.6000 ;
      RECT 0.0000 85.9800 123.5500 86.6000 ;
      RECT 0.0000 0.6200 712.6000 85.9800 ;
      RECT 682.8500 0.0000 712.6000 0.6200 ;
      RECT 674.6500 0.0000 682.5500 0.6200 ;
      RECT 673.0500 0.0000 674.3500 0.6200 ;
      RECT 665.6500 0.0000 672.7500 0.6200 ;
      RECT 663.2500 0.0000 665.3500 0.6200 ;
      RECT 652.4500 0.0000 662.9500 0.6200 ;
      RECT 649.8500 0.0000 652.1500 0.6200 ;
      RECT 649.4500 0.0000 649.5500 0.6200 ;
      RECT 646.6500 0.0000 649.1500 0.6200 ;
      RECT 637.4500 0.0000 646.3500 0.6200 ;
      RECT 632.0500 0.0000 637.1500 0.6200 ;
      RECT 629.6500 0.0000 631.7500 0.6200 ;
      RECT 626.8500 0.0000 629.3500 0.6200 ;
      RECT 621.4500 0.0000 626.5500 0.6200 ;
      RECT 610.0500 0.0000 621.1500 0.6200 ;
      RECT 609.2500 0.0000 609.7500 0.6200 ;
      RECT 603.8500 0.0000 608.9500 0.6200 ;
      RECT 599.4500 0.0000 603.5500 0.6200 ;
      RECT 588.6500 0.0000 599.1500 0.6200 ;
      RECT 588.2500 0.0000 588.3500 0.6200 ;
      RECT 586.2500 0.0000 587.9500 0.6200 ;
      RECT 581.2500 0.0000 585.9500 0.6200 ;
      RECT 566.2500 0.0000 580.9500 0.6200 ;
      RECT 564.6500 0.0000 565.9500 0.6200 ;
      RECT 556.2500 0.0000 564.3500 0.6200 ;
      RECT 552.4500 0.0000 555.9500 0.6200 ;
      RECT 550.8500 0.0000 552.1500 0.6200 ;
      RECT 546.2500 0.0000 550.5500 0.6200 ;
      RECT 544.8500 0.0000 545.9500 0.6200 ;
      RECT 536.0500 0.0000 544.5500 0.6200 ;
      RECT 524.0500 0.0000 535.7500 0.6200 ;
      RECT 523.6500 0.0000 523.7500 0.6200 ;
      RECT 522.6500 0.0000 523.3500 0.6200 ;
      RECT 521.0500 0.0000 522.3500 0.6200 ;
      RECT 513.6500 0.0000 520.7500 0.6200 ;
      RECT 512.2500 0.0000 513.3500 0.6200 ;
      RECT 511.8500 0.0000 511.9500 0.6200 ;
      RECT 508.2500 0.0000 511.5500 0.6200 ;
      RECT 502.0500 0.0000 507.9500 0.6200 ;
      RECT 500.2500 0.0000 501.7500 0.6200 ;
      RECT 495.2500 0.0000 499.9500 0.6200 ;
      RECT 491.4500 0.0000 494.9500 0.6200 ;
      RECT 479.8500 0.0000 491.1500 0.6200 ;
      RECT 478.8500 0.0000 479.5500 0.6200 ;
      RECT 475.2500 0.0000 478.5500 0.6200 ;
      RECT 469.6500 0.0000 474.9500 0.6200 ;
      RECT 463.8500 0.0000 469.3500 0.6200 ;
      RECT 458.0500 0.0000 463.5500 0.6200 ;
      RECT 454.6500 0.0000 457.7500 0.6200 ;
      RECT 452.6500 0.0000 454.3500 0.6200 ;
      RECT 451.0500 0.0000 452.3500 0.6200 ;
      RECT 436.0500 0.0000 450.7500 0.6200 ;
      RECT 433.8500 0.0000 435.7500 0.6200 ;
      RECT 430.8500 0.0000 433.5500 0.6200 ;
      RECT 426.4500 0.0000 430.5500 0.6200 ;
      RECT 425.2500 0.0000 426.1500 0.6200 ;
      RECT 424.4500 0.0000 424.9500 0.6200 ;
      RECT 422.8500 0.0000 424.1500 0.6200 ;
      RECT 419.8500 0.0000 422.5500 0.6200 ;
      RECT 405.8500 0.0000 419.5500 0.6200 ;
      RECT 405.2500 0.0000 405.5500 0.6200 ;
      RECT 393.2500 0.0000 404.9500 0.6200 ;
      RECT 392.6500 0.0000 392.9500 0.6200 ;
      RECT 390.8500 0.0000 392.3500 0.6200 ;
      RECT 387.4500 0.0000 390.5500 0.6200 ;
      RECT 377.6500 0.0000 387.1500 0.6200 ;
      RECT 372.0500 0.0000 377.3500 0.6200 ;
      RECT 368.4500 0.0000 371.7500 0.6200 ;
      RECT 363.0500 0.0000 368.1500 0.6200 ;
      RECT 350.0500 0.0000 362.7500 0.6200 ;
      RECT 347.2500 0.0000 349.7500 0.6200 ;
      RECT 342.4500 0.0000 346.9500 0.6200 ;
      RECT 338.6500 0.0000 342.1500 0.6200 ;
      RECT 332.2500 0.0000 338.3500 0.6200 ;
      RECT 323.6500 0.0000 331.9500 0.6200 ;
      RECT 323.0500 0.0000 323.3500 0.6200 ;
      RECT 322.4500 0.0000 322.7500 0.6200 ;
      RECT 309.6500 0.0000 322.1500 0.6200 ;
      RECT 307.2500 0.0000 309.3500 0.6200 ;
      RECT 306.0500 0.0000 306.9500 0.6200 ;
      RECT 301.4500 0.0000 305.7500 0.6200 ;
      RECT 296.8500 0.0000 301.1500 0.6200 ;
      RECT 291.2500 0.0000 296.5500 0.6200 ;
      RECT 285.6500 0.0000 290.9500 0.6200 ;
      RECT 281.6500 0.0000 285.3500 0.6200 ;
      RECT 280.4500 0.0000 281.3500 0.6200 ;
      RECT 265.4500 0.0000 280.1500 0.6200 ;
      RECT 263.2500 0.0000 265.1500 0.6200 ;
      RECT 261.8500 0.0000 262.9500 0.6200 ;
      RECT 253.2500 0.0000 261.5500 0.6200 ;
      RECT 252.8500 0.0000 252.9500 0.6200 ;
      RECT 242.6500 0.0000 252.5500 0.6200 ;
      RECT 241.0500 0.0000 242.3500 0.6200 ;
      RECT 237.4500 0.0000 240.7500 0.6200 ;
      RECT 179.0500 0.0000 237.1500 0.6200 ;
      RECT 177.6500 0.0000 178.7500 0.6200 ;
      RECT 176.0500 0.0000 177.3500 0.6200 ;
      RECT 172.0500 0.0000 175.7500 0.6200 ;
      RECT 166.8500 0.0000 171.7500 0.6200 ;
      RECT 156.8500 0.0000 166.5500 0.6200 ;
      RECT 155.2500 0.0000 156.5500 0.6200 ;
      RECT 154.0500 0.0000 154.9500 0.6200 ;
      RECT 149.0500 0.0000 153.7500 0.6200 ;
      RECT 132.4500 0.0000 148.7500 0.6200 ;
      RECT 128.0500 0.0000 132.1500 0.6200 ;
      RECT 121.4500 0.0000 127.7500 0.6200 ;
      RECT 120.8500 0.0000 121.1500 0.6200 ;
      RECT 113.0500 0.0000 120.5500 0.6200 ;
      RECT 0.0000 0.0000 112.7500 0.6200 ;
    LAYER M3 ;
      RECT 0.0000 66.3500 712.6000 86.6000 ;
      RECT 0.0000 66.0500 711.9800 66.3500 ;
      RECT 0.0000 63.5500 712.6000 66.0500 ;
      RECT 0.0000 63.2500 711.9800 63.5500 ;
      RECT 0.0000 53.9500 712.6000 63.2500 ;
      RECT 0.0000 53.6500 711.9800 53.9500 ;
      RECT 0.0000 52.7500 712.6000 53.6500 ;
      RECT 0.0000 52.4500 711.9800 52.7500 ;
      RECT 0.0000 49.7500 712.6000 52.4500 ;
      RECT 0.0000 49.4500 711.9800 49.7500 ;
      RECT 0.0000 41.5500 712.6000 49.4500 ;
      RECT 0.6200 41.2500 712.6000 41.5500 ;
      RECT 0.0000 35.9500 712.6000 41.2500 ;
      RECT 0.0000 35.6500 711.9800 35.9500 ;
      RECT 0.0000 33.1500 712.6000 35.6500 ;
      RECT 0.0000 32.8500 711.9800 33.1500 ;
      RECT 0.0000 28.7500 712.6000 32.8500 ;
      RECT 0.0000 28.4500 711.9800 28.7500 ;
      RECT 0.0000 27.5500 712.6000 28.4500 ;
      RECT 0.0000 27.2500 711.9800 27.5500 ;
      RECT 0.0000 21.7500 712.6000 27.2500 ;
      RECT 0.0000 21.4500 711.9800 21.7500 ;
      RECT 0.0000 0.0000 712.6000 21.4500 ;
    LAYER M4 ;
      RECT 696.6500 85.9800 712.6000 86.6000 ;
      RECT 653.6500 85.9800 696.3500 86.6000 ;
      RECT 647.6500 85.9800 653.3500 86.6000 ;
      RECT 609.2500 85.9800 647.3500 86.6000 ;
      RECT 555.0500 85.9800 608.9500 86.6000 ;
      RECT 480.4500 85.9800 554.7500 86.6000 ;
      RECT 372.4500 85.9800 480.1500 86.6000 ;
      RECT 295.6500 85.9800 372.1500 86.6000 ;
      RECT 219.8500 85.9800 295.3500 86.6000 ;
      RECT 177.2500 85.9800 219.5500 86.6000 ;
      RECT 0.0000 85.9800 176.9500 86.6000 ;
      RECT 0.0000 0.6200 712.6000 85.9800 ;
      RECT 632.0500 0.0000 712.6000 0.6200 ;
      RECT 599.6500 0.0000 631.7500 0.6200 ;
      RECT 479.6500 0.0000 599.3500 0.6200 ;
      RECT 347.4500 0.0000 479.3500 0.6200 ;
      RECT 285.6500 0.0000 347.1500 0.6200 ;
      RECT 237.2500 0.0000 285.3500 0.6200 ;
      RECT 112.8500 0.0000 236.9500 0.6200 ;
      RECT 0.0000 0.0000 112.5500 0.6200 ;
  END
END sram_128b_w16

END LIBRARY
